VERSION 5.7 ;
  NOWIREEXTENSIONATPIN ON ;
  DIVIDERCHAR "/" ;
  BUSBITCHARS "[]" ;
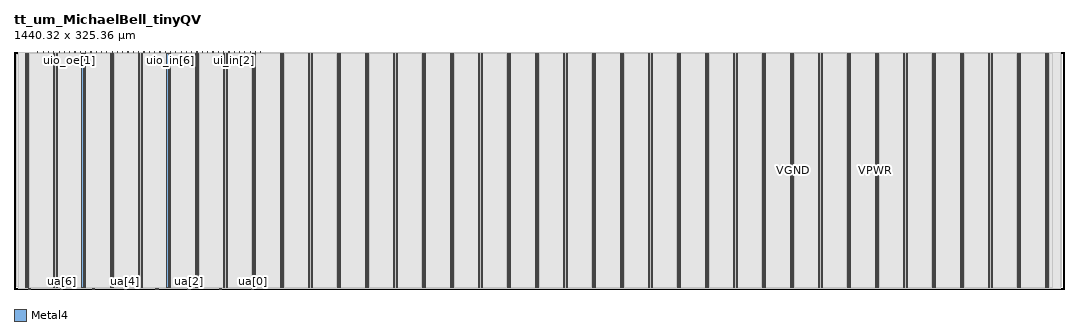
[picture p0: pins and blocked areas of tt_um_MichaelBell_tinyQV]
MACRO tt_um_MichaelBell_tinyQV
  CLASS BLOCK ;
  FOREIGN tt_um_MichaelBell_tinyQV ;
  ORIGIN 0.000 0.000 ;
  SIZE 1440.320 BY 325.360 ;
  PIN VGND
    DIRECTION INOUT ;
    USE GROUND ;
    PORT
      LAYER Metal4 ;
        RECT 18.820 2.000 20.420 323.360 ;
    END
    PORT
      LAYER Metal4 ;
        RECT 57.690 2.000 59.290 323.360 ;
    END
    PORT
      LAYER Metal4 ;
        RECT 96.560 2.000 98.160 323.360 ;
    END
    PORT
      LAYER Metal4 ;
        RECT 135.430 2.000 137.030 323.360 ;
    END
    PORT
      LAYER Metal4 ;
        RECT 174.300 2.000 175.900 323.360 ;
    END
    PORT
      LAYER Metal4 ;
        RECT 213.170 2.000 214.770 323.360 ;
    END
    PORT
      LAYER Metal4 ;
        RECT 252.040 2.000 253.640 323.360 ;
    END
    PORT
      LAYER Metal4 ;
        RECT 290.910 2.000 292.510 323.360 ;
    END
    PORT
      LAYER Metal4 ;
        RECT 329.780 2.000 331.380 323.360 ;
    END
    PORT
      LAYER Metal4 ;
        RECT 368.650 2.000 370.250 323.360 ;
    END
    PORT
      LAYER Metal4 ;
        RECT 407.520 2.000 409.120 323.360 ;
    END
    PORT
      LAYER Metal4 ;
        RECT 446.390 2.000 447.990 323.360 ;
    END
    PORT
      LAYER Metal4 ;
        RECT 485.260 2.000 486.860 323.360 ;
    END
    PORT
      LAYER Metal4 ;
        RECT 524.130 2.000 525.730 323.360 ;
    END
    PORT
      LAYER Metal4 ;
        RECT 563.000 2.000 564.600 323.360 ;
    END
    PORT
      LAYER Metal4 ;
        RECT 601.870 2.000 603.470 323.360 ;
    END
    PORT
      LAYER Metal4 ;
        RECT 640.740 2.000 642.340 323.360 ;
    END
    PORT
      LAYER Metal4 ;
        RECT 679.610 2.000 681.210 323.360 ;
    END
    PORT
      LAYER Metal4 ;
        RECT 718.480 2.000 720.080 323.360 ;
    END
    PORT
      LAYER Metal4 ;
        RECT 757.350 2.000 758.950 323.360 ;
    END
    PORT
      LAYER Metal4 ;
        RECT 796.220 2.000 797.820 323.360 ;
    END
    PORT
      LAYER Metal4 ;
        RECT 835.090 2.000 836.690 323.360 ;
    END
    PORT
      LAYER Metal4 ;
        RECT 873.960 2.000 875.560 323.360 ;
    END
    PORT
      LAYER Metal4 ;
        RECT 912.830 2.000 914.430 323.360 ;
    END
    PORT
      LAYER Metal4 ;
        RECT 951.700 2.000 953.300 323.360 ;
    END
    PORT
      LAYER Metal4 ;
        RECT 990.570 2.000 992.170 323.360 ;
    END
    PORT
      LAYER Metal4 ;
        RECT 1029.440 2.000 1031.040 323.360 ;
    END
    PORT
      LAYER Metal4 ;
        RECT 1068.310 2.000 1069.910 323.360 ;
    END
    PORT
      LAYER Metal4 ;
        RECT 1107.180 2.000 1108.780 323.360 ;
    END
    PORT
      LAYER Metal4 ;
        RECT 1146.050 2.000 1147.650 323.360 ;
    END
    PORT
      LAYER Metal4 ;
        RECT 1184.920 2.000 1186.520 323.360 ;
    END
    PORT
      LAYER Metal4 ;
        RECT 1223.790 2.000 1225.390 323.360 ;
    END
    PORT
      LAYER Metal4 ;
        RECT 1262.660 2.000 1264.260 323.360 ;
    END
    PORT
      LAYER Metal4 ;
        RECT 1301.530 2.000 1303.130 323.360 ;
    END
    PORT
      LAYER Metal4 ;
        RECT 1340.400 2.000 1342.000 323.360 ;
    END
    PORT
      LAYER Metal4 ;
        RECT 1379.270 2.000 1380.870 323.360 ;
    END
    PORT
      LAYER Metal4 ;
        RECT 1418.140 2.000 1419.740 323.360 ;
    END
  END VGND
  PIN VPWR
    DIRECTION INOUT ;
    USE POWER ;
    PORT
      LAYER Metal4 ;
        RECT 15.520 2.000 17.120 323.360 ;
    END
    PORT
      LAYER Metal4 ;
        RECT 54.390 2.000 55.990 323.360 ;
    END
    PORT
      LAYER Metal4 ;
        RECT 93.260 2.000 94.860 323.360 ;
    END
    PORT
      LAYER Metal4 ;
        RECT 132.130 2.000 133.730 323.360 ;
    END
    PORT
      LAYER Metal4 ;
        RECT 171.000 2.000 172.600 323.360 ;
    END
    PORT
      LAYER Metal4 ;
        RECT 209.870 2.000 211.470 323.360 ;
    END
    PORT
      LAYER Metal4 ;
        RECT 248.740 2.000 250.340 323.360 ;
    END
    PORT
      LAYER Metal4 ;
        RECT 287.610 2.000 289.210 323.360 ;
    END
    PORT
      LAYER Metal4 ;
        RECT 326.480 2.000 328.080 323.360 ;
    END
    PORT
      LAYER Metal4 ;
        RECT 365.350 2.000 366.950 323.360 ;
    END
    PORT
      LAYER Metal4 ;
        RECT 404.220 2.000 405.820 323.360 ;
    END
    PORT
      LAYER Metal4 ;
        RECT 443.090 2.000 444.690 323.360 ;
    END
    PORT
      LAYER Metal4 ;
        RECT 481.960 2.000 483.560 323.360 ;
    END
    PORT
      LAYER Metal4 ;
        RECT 520.830 2.000 522.430 323.360 ;
    END
    PORT
      LAYER Metal4 ;
        RECT 559.700 2.000 561.300 323.360 ;
    END
    PORT
      LAYER Metal4 ;
        RECT 598.570 2.000 600.170 323.360 ;
    END
    PORT
      LAYER Metal4 ;
        RECT 637.440 2.000 639.040 323.360 ;
    END
    PORT
      LAYER Metal4 ;
        RECT 676.310 2.000 677.910 323.360 ;
    END
    PORT
      LAYER Metal4 ;
        RECT 715.180 2.000 716.780 323.360 ;
    END
    PORT
      LAYER Metal4 ;
        RECT 754.050 2.000 755.650 323.360 ;
    END
    PORT
      LAYER Metal4 ;
        RECT 792.920 2.000 794.520 323.360 ;
    END
    PORT
      LAYER Metal4 ;
        RECT 831.790 2.000 833.390 323.360 ;
    END
    PORT
      LAYER Metal4 ;
        RECT 870.660 2.000 872.260 323.360 ;
    END
    PORT
      LAYER Metal4 ;
        RECT 909.530 2.000 911.130 323.360 ;
    END
    PORT
      LAYER Metal4 ;
        RECT 948.400 2.000 950.000 323.360 ;
    END
    PORT
      LAYER Metal4 ;
        RECT 987.270 2.000 988.870 323.360 ;
    END
    PORT
      LAYER Metal4 ;
        RECT 1026.140 2.000 1027.740 323.360 ;
    END
    PORT
      LAYER Metal4 ;
        RECT 1065.010 2.000 1066.610 323.360 ;
    END
    PORT
      LAYER Metal4 ;
        RECT 1103.880 2.000 1105.480 323.360 ;
    END
    PORT
      LAYER Metal4 ;
        RECT 1142.750 2.000 1144.350 323.360 ;
    END
    PORT
      LAYER Metal4 ;
        RECT 1181.620 2.000 1183.220 323.360 ;
    END
    PORT
      LAYER Metal4 ;
        RECT 1220.490 2.000 1222.090 323.360 ;
    END
    PORT
      LAYER Metal4 ;
        RECT 1259.360 2.000 1260.960 323.360 ;
    END
    PORT
      LAYER Metal4 ;
        RECT 1298.230 2.000 1299.830 323.360 ;
    END
    PORT
      LAYER Metal4 ;
        RECT 1337.100 2.000 1338.700 323.360 ;
    END
    PORT
      LAYER Metal4 ;
        RECT 1375.970 2.000 1377.570 323.360 ;
    END
    PORT
      LAYER Metal4 ;
        RECT 1414.840 2.000 1416.440 323.360 ;
    END
  END VPWR
  PIN clk
    DIRECTION INPUT ;
    USE SIGNAL ;
    ANTENNAGATEAREA 4.738000 ;
    PORT
      LAYER Metal4 ;
        RECT 331.090 324.360 331.390 325.360 ;
    END
  END clk
  PIN ena
    DIRECTION INPUT ;
    USE SIGNAL ;
    PORT
      LAYER Metal4 ;
        RECT 338.370 324.360 338.670 325.360 ;
    END
  END ena
  PIN rst_n
    DIRECTION INPUT ;
    USE SIGNAL ;
    ANTENNAGATEAREA 1.102000 ;
    PORT
      LAYER Metal4 ;
        RECT 323.810 324.360 324.110 325.360 ;
    END
  END rst_n
  PIN ua[0]
    DIRECTION INOUT ;
    USE SIGNAL ;
    PORT
      LAYER Metal4 ;
        RECT 325.820 0.000 328.820 1.000 ;
    END
  END ua[0]
  PIN ua[1]
    DIRECTION INOUT ;
    USE SIGNAL ;
    PORT
      LAYER Metal4 ;
        RECT 282.140 0.000 285.140 1.000 ;
    END
  END ua[1]
  PIN ua[2]
    DIRECTION INOUT ;
    USE SIGNAL ;
    PORT
      LAYER Metal4 ;
        RECT 238.460 0.000 241.460 1.000 ;
    END
  END ua[2]
  PIN ua[3]
    DIRECTION INOUT ;
    USE SIGNAL ;
    PORT
      LAYER Metal4 ;
        RECT 194.780 0.000 197.780 1.000 ;
    END
  END ua[3]
  PIN ua[4]
    DIRECTION INOUT ;
    USE SIGNAL ;
    PORT
      LAYER Metal4 ;
        RECT 151.100 0.000 154.100 1.000 ;
    END
  END ua[4]
  PIN ua[5]
    DIRECTION INOUT ;
    USE SIGNAL ;
    PORT
      LAYER Metal4 ;
        RECT 107.420 0.000 110.420 1.000 ;
    END
  END ua[5]
  PIN ua[6]
    DIRECTION INOUT ;
    USE SIGNAL ;
    PORT
      LAYER Metal4 ;
        RECT 63.740 0.000 66.740 1.000 ;
    END
  END ua[6]
  PIN ua[7]
    DIRECTION INOUT ;
    USE SIGNAL ;
    PORT
      LAYER Metal4 ;
        RECT 20.060 0.000 23.060 1.000 ;
    END
  END ua[7]
  PIN ui_in[0]
    DIRECTION INPUT ;
    USE SIGNAL ;
    ANTENNAGATEAREA 0.498500 ;
    PORT
      LAYER Metal4 ;
        RECT 316.530 324.360 316.830 325.360 ;
    END
  END ui_in[0]
  PIN ui_in[1]
    DIRECTION INPUT ;
    USE SIGNAL ;
    ANTENNAGATEAREA 0.498500 ;
    PORT
      LAYER Metal4 ;
        RECT 309.250 324.360 309.550 325.360 ;
    END
  END ui_in[1]
  PIN ui_in[2]
    DIRECTION INPUT ;
    USE SIGNAL ;
    ANTENNAGATEAREA 0.498500 ;
    PORT
      LAYER Metal4 ;
        RECT 301.970 324.360 302.270 325.360 ;
    END
  END ui_in[2]
  PIN ui_in[3]
    DIRECTION INPUT ;
    USE SIGNAL ;
    ANTENNAGATEAREA 1.102000 ;
    PORT
      LAYER Metal4 ;
        RECT 294.690 324.360 294.990 325.360 ;
    END
  END ui_in[3]
  PIN ui_in[4]
    DIRECTION INPUT ;
    USE SIGNAL ;
    ANTENNAGATEAREA 1.102000 ;
    PORT
      LAYER Metal4 ;
        RECT 287.410 324.360 287.710 325.360 ;
    END
  END ui_in[4]
  PIN ui_in[5]
    DIRECTION INPUT ;
    USE SIGNAL ;
    ANTENNAGATEAREA 1.102000 ;
    PORT
      LAYER Metal4 ;
        RECT 280.130 324.360 280.430 325.360 ;
    END
  END ui_in[5]
  PIN ui_in[6]
    DIRECTION INPUT ;
    USE SIGNAL ;
    ANTENNAGATEAREA 0.498500 ;
    PORT
      LAYER Metal4 ;
        RECT 272.850 324.360 273.150 325.360 ;
    END
  END ui_in[6]
  PIN ui_in[7]
    DIRECTION INPUT ;
    USE SIGNAL ;
    ANTENNAGATEAREA 0.498500 ;
    PORT
      LAYER Metal4 ;
        RECT 265.570 324.360 265.870 325.360 ;
    END
  END ui_in[7]
  PIN uio_in[0]
    DIRECTION INPUT ;
    USE SIGNAL ;
    PORT
      LAYER Metal4 ;
        RECT 258.290 324.360 258.590 325.360 ;
    END
  END uio_in[0]
  PIN uio_in[1]
    DIRECTION INPUT ;
    USE SIGNAL ;
    ANTENNAGATEAREA 0.498500 ;
    PORT
      LAYER Metal4 ;
        RECT 251.010 324.360 251.310 325.360 ;
    END
  END uio_in[1]
  PIN uio_in[2]
    DIRECTION INPUT ;
    USE SIGNAL ;
    ANTENNAGATEAREA 0.498500 ;
    PORT
      LAYER Metal4 ;
        RECT 243.730 324.360 244.030 325.360 ;
    END
  END uio_in[2]
  PIN uio_in[3]
    DIRECTION INPUT ;
    USE SIGNAL ;
    PORT
      LAYER Metal4 ;
        RECT 236.450 324.360 236.750 325.360 ;
    END
  END uio_in[3]
  PIN uio_in[4]
    DIRECTION INPUT ;
    USE SIGNAL ;
    ANTENNAGATEAREA 0.498500 ;
    PORT
      LAYER Metal4 ;
        RECT 229.170 324.360 229.470 325.360 ;
    END
  END uio_in[4]
  PIN uio_in[5]
    DIRECTION INPUT ;
    USE SIGNAL ;
    ANTENNAGATEAREA 0.498500 ;
    PORT
      LAYER Metal4 ;
        RECT 221.890 324.360 222.190 325.360 ;
    END
  END uio_in[5]
  PIN uio_in[6]
    DIRECTION INPUT ;
    USE SIGNAL ;
    PORT
      LAYER Metal4 ;
        RECT 214.610 324.360 214.910 325.360 ;
    END
  END uio_in[6]
  PIN uio_in[7]
    DIRECTION INPUT ;
    USE SIGNAL ;
    PORT
      LAYER Metal4 ;
        RECT 207.330 324.360 207.630 325.360 ;
    END
  END uio_in[7]
  PIN uio_oe[0]
    DIRECTION OUTPUT ;
    USE SIGNAL ;
    ANTENNADIFFAREA 1.182800 ;
    PORT
      LAYER Metal4 ;
        RECT 83.570 324.360 83.870 325.360 ;
    END
  END uio_oe[0]
  PIN uio_oe[1]
    DIRECTION OUTPUT ;
    USE SIGNAL ;
    ANTENNADIFFAREA 3.879200 ;
    PORT
      LAYER Metal4 ;
        RECT 76.290 324.360 76.590 325.360 ;
    END
  END uio_oe[1]
  PIN uio_oe[2]
    DIRECTION OUTPUT ;
    USE SIGNAL ;
    ANTENNAGATEAREA 0.741000 ;
    ANTENNADIFFAREA 2.080400 ;
    PORT
      LAYER Metal4 ;
        RECT 69.010 324.360 69.310 325.360 ;
    END
  END uio_oe[2]
  PIN uio_oe[3]
    DIRECTION OUTPUT ;
    USE SIGNAL ;
    ANTENNADIFFAREA 1.182800 ;
    PORT
      LAYER Metal4 ;
        RECT 61.730 324.360 62.030 325.360 ;
    END
  END uio_oe[3]
  PIN uio_oe[4]
    DIRECTION OUTPUT ;
    USE SIGNAL ;
    ANTENNADIFFAREA 1.182800 ;
    PORT
      LAYER Metal4 ;
        RECT 54.450 324.360 54.750 325.360 ;
    END
  END uio_oe[4]
  PIN uio_oe[5]
    DIRECTION OUTPUT ;
    USE SIGNAL ;
    ANTENNADIFFAREA 1.182800 ;
    PORT
      LAYER Metal4 ;
        RECT 47.170 324.360 47.470 325.360 ;
    END
  END uio_oe[5]
  PIN uio_oe[6]
    DIRECTION OUTPUT ;
    USE SIGNAL ;
    ANTENNADIFFAREA 1.182800 ;
    PORT
      LAYER Metal4 ;
        RECT 39.890 324.360 40.190 325.360 ;
    END
  END uio_oe[6]
  PIN uio_oe[7]
    DIRECTION OUTPUT ;
    USE SIGNAL ;
    ANTENNADIFFAREA 1.182800 ;
    PORT
      LAYER Metal4 ;
        RECT 32.610 324.360 32.910 325.360 ;
    END
  END uio_oe[7]
  PIN uio_out[0]
    DIRECTION OUTPUT ;
    USE SIGNAL ;
    ANTENNADIFFAREA 1.182800 ;
    PORT
      LAYER Metal4 ;
        RECT 141.810 324.360 142.110 325.360 ;
    END
  END uio_out[0]
  PIN uio_out[1]
    DIRECTION OUTPUT ;
    USE SIGNAL ;
    ANTENNADIFFAREA 1.366000 ;
    PORT
      LAYER Metal4 ;
        RECT 134.530 324.360 134.830 325.360 ;
    END
  END uio_out[1]
  PIN uio_out[2]
    DIRECTION OUTPUT ;
    USE SIGNAL ;
    ANTENNADIFFAREA 1.366000 ;
    PORT
      LAYER Metal4 ;
        RECT 127.250 324.360 127.550 325.360 ;
    END
  END uio_out[2]
  PIN uio_out[3]
    DIRECTION OUTPUT ;
    USE SIGNAL ;
    ANTENNADIFFAREA 1.182800 ;
    PORT
      LAYER Metal4 ;
        RECT 119.970 324.360 120.270 325.360 ;
    END
  END uio_out[3]
  PIN uio_out[4]
    DIRECTION OUTPUT ;
    USE SIGNAL ;
    ANTENNADIFFAREA 2.932000 ;
    PORT
      LAYER Metal4 ;
        RECT 112.690 324.360 112.990 325.360 ;
    END
  END uio_out[4]
  PIN uio_out[5]
    DIRECTION OUTPUT ;
    USE SIGNAL ;
    ANTENNADIFFAREA 1.366000 ;
    PORT
      LAYER Metal4 ;
        RECT 105.410 324.360 105.710 325.360 ;
    END
  END uio_out[5]
  PIN uio_out[6]
    DIRECTION OUTPUT ;
    USE SIGNAL ;
    ANTENNADIFFAREA 1.182800 ;
    PORT
      LAYER Metal4 ;
        RECT 98.130 324.360 98.430 325.360 ;
    END
  END uio_out[6]
  PIN uio_out[7]
    DIRECTION OUTPUT ;
    USE SIGNAL ;
    ANTENNADIFFAREA 4.389000 ;
    PORT
      LAYER Metal4 ;
        RECT 90.850 324.360 91.150 325.360 ;
    END
  END uio_out[7]
  PIN uo_out[0]
    DIRECTION OUTPUT ;
    USE SIGNAL ;
    ANTENNADIFFAREA 4.369000 ;
    PORT
      LAYER Metal4 ;
        RECT 200.050 324.360 200.350 325.360 ;
    END
  END uo_out[0]
  PIN uo_out[1]
    DIRECTION OUTPUT ;
    USE SIGNAL ;
    ANTENNADIFFAREA 4.369000 ;
    PORT
      LAYER Metal4 ;
        RECT 192.770 324.360 193.070 325.360 ;
    END
  END uo_out[1]
  PIN uo_out[2]
    DIRECTION OUTPUT ;
    USE SIGNAL ;
    ANTENNADIFFAREA 1.121800 ;
    PORT
      LAYER Metal4 ;
        RECT 185.490 324.360 185.790 325.360 ;
    END
  END uo_out[2]
  PIN uo_out[3]
    DIRECTION OUTPUT ;
    USE SIGNAL ;
    ANTENNADIFFAREA 1.121800 ;
    PORT
      LAYER Metal4 ;
        RECT 178.210 324.360 178.510 325.360 ;
    END
  END uo_out[3]
  PIN uo_out[4]
    DIRECTION OUTPUT ;
    USE SIGNAL ;
    ANTENNADIFFAREA 1.121800 ;
    PORT
      LAYER Metal4 ;
        RECT 170.930 324.360 171.230 325.360 ;
    END
  END uo_out[4]
  PIN uo_out[5]
    DIRECTION OUTPUT ;
    USE SIGNAL ;
    ANTENNADIFFAREA 1.121800 ;
    PORT
      LAYER Metal4 ;
        RECT 163.650 324.360 163.950 325.360 ;
    END
  END uo_out[5]
  PIN uo_out[6]
    DIRECTION OUTPUT ;
    USE SIGNAL ;
    ANTENNADIFFAREA 1.366000 ;
    PORT
      LAYER Metal4 ;
        RECT 156.370 324.360 156.670 325.360 ;
    END
  END uo_out[6]
  PIN uo_out[7]
    DIRECTION OUTPUT ;
    USE SIGNAL ;
    ANTENNADIFFAREA 1.121800 ;
    PORT
      LAYER Metal4 ;
        RECT 149.090 324.360 149.390 325.360 ;
    END
  END uo_out[7]
  OBS
      LAYER Nwell ;
        RECT 2.930 319.280 1437.390 321.870 ;
      LAYER Pwell ;
        RECT 2.930 315.760 1437.390 319.280 ;
      LAYER Nwell ;
        RECT 2.930 311.440 1437.390 315.760 ;
      LAYER Pwell ;
        RECT 2.930 307.920 1437.390 311.440 ;
      LAYER Nwell ;
        RECT 2.930 303.600 1437.390 307.920 ;
      LAYER Pwell ;
        RECT 2.930 300.080 1437.390 303.600 ;
      LAYER Nwell ;
        RECT 2.930 295.760 1437.390 300.080 ;
      LAYER Pwell ;
        RECT 2.930 292.240 1437.390 295.760 ;
      LAYER Nwell ;
        RECT 2.930 287.920 1437.390 292.240 ;
      LAYER Pwell ;
        RECT 2.930 284.400 1437.390 287.920 ;
      LAYER Nwell ;
        RECT 2.930 280.080 1437.390 284.400 ;
      LAYER Pwell ;
        RECT 2.930 276.560 1437.390 280.080 ;
      LAYER Nwell ;
        RECT 2.930 272.240 1437.390 276.560 ;
      LAYER Pwell ;
        RECT 2.930 268.720 1437.390 272.240 ;
      LAYER Nwell ;
        RECT 2.930 264.400 1437.390 268.720 ;
      LAYER Pwell ;
        RECT 2.930 260.880 1437.390 264.400 ;
      LAYER Nwell ;
        RECT 2.930 256.560 1437.390 260.880 ;
      LAYER Pwell ;
        RECT 2.930 253.040 1437.390 256.560 ;
      LAYER Nwell ;
        RECT 2.930 248.720 1437.390 253.040 ;
      LAYER Pwell ;
        RECT 2.930 245.200 1437.390 248.720 ;
      LAYER Nwell ;
        RECT 2.930 240.880 1437.390 245.200 ;
      LAYER Pwell ;
        RECT 2.930 237.360 1437.390 240.880 ;
      LAYER Nwell ;
        RECT 2.930 233.040 1437.390 237.360 ;
      LAYER Pwell ;
        RECT 2.930 229.520 1437.390 233.040 ;
      LAYER Nwell ;
        RECT 2.930 225.200 1437.390 229.520 ;
      LAYER Pwell ;
        RECT 2.930 221.680 1437.390 225.200 ;
      LAYER Nwell ;
        RECT 2.930 217.360 1437.390 221.680 ;
      LAYER Pwell ;
        RECT 2.930 213.840 1437.390 217.360 ;
      LAYER Nwell ;
        RECT 2.930 209.520 1437.390 213.840 ;
      LAYER Pwell ;
        RECT 2.930 206.000 1437.390 209.520 ;
      LAYER Nwell ;
        RECT 2.930 201.680 1437.390 206.000 ;
      LAYER Pwell ;
        RECT 2.930 198.160 1437.390 201.680 ;
      LAYER Nwell ;
        RECT 2.930 193.840 1437.390 198.160 ;
      LAYER Pwell ;
        RECT 2.930 190.320 1437.390 193.840 ;
      LAYER Nwell ;
        RECT 2.930 186.000 1437.390 190.320 ;
      LAYER Pwell ;
        RECT 2.930 182.480 1437.390 186.000 ;
      LAYER Nwell ;
        RECT 2.930 178.160 1437.390 182.480 ;
      LAYER Pwell ;
        RECT 2.930 174.640 1437.390 178.160 ;
      LAYER Nwell ;
        RECT 2.930 170.320 1437.390 174.640 ;
      LAYER Pwell ;
        RECT 2.930 166.800 1437.390 170.320 ;
      LAYER Nwell ;
        RECT 2.930 162.480 1437.390 166.800 ;
      LAYER Pwell ;
        RECT 2.930 158.960 1437.390 162.480 ;
      LAYER Nwell ;
        RECT 2.930 154.640 1437.390 158.960 ;
      LAYER Pwell ;
        RECT 2.930 151.120 1437.390 154.640 ;
      LAYER Nwell ;
        RECT 2.930 146.800 1437.390 151.120 ;
      LAYER Pwell ;
        RECT 2.930 143.280 1437.390 146.800 ;
      LAYER Nwell ;
        RECT 2.930 138.960 1437.390 143.280 ;
      LAYER Pwell ;
        RECT 2.930 135.440 1437.390 138.960 ;
      LAYER Nwell ;
        RECT 2.930 131.120 1437.390 135.440 ;
      LAYER Pwell ;
        RECT 2.930 127.600 1437.390 131.120 ;
      LAYER Nwell ;
        RECT 2.930 123.280 1437.390 127.600 ;
      LAYER Pwell ;
        RECT 2.930 119.760 1437.390 123.280 ;
      LAYER Nwell ;
        RECT 2.930 115.440 1437.390 119.760 ;
      LAYER Pwell ;
        RECT 2.930 111.920 1437.390 115.440 ;
      LAYER Nwell ;
        RECT 2.930 107.600 1437.390 111.920 ;
      LAYER Pwell ;
        RECT 2.930 104.080 1437.390 107.600 ;
      LAYER Nwell ;
        RECT 2.930 99.760 1437.390 104.080 ;
      LAYER Pwell ;
        RECT 2.930 96.240 1437.390 99.760 ;
      LAYER Nwell ;
        RECT 2.930 91.920 1437.390 96.240 ;
      LAYER Pwell ;
        RECT 2.930 88.400 1437.390 91.920 ;
      LAYER Nwell ;
        RECT 2.930 84.080 1437.390 88.400 ;
      LAYER Pwell ;
        RECT 2.930 80.560 1437.390 84.080 ;
      LAYER Nwell ;
        RECT 2.930 76.240 1437.390 80.560 ;
      LAYER Pwell ;
        RECT 2.930 72.720 1437.390 76.240 ;
      LAYER Nwell ;
        RECT 2.930 68.400 1437.390 72.720 ;
      LAYER Pwell ;
        RECT 2.930 66.210 1437.390 68.400 ;
        RECT 2.930 64.880 266.430 66.210 ;
      LAYER Nwell ;
        RECT 266.430 64.880 1437.390 66.210 ;
        RECT 2.930 60.560 1437.390 64.880 ;
      LAYER Pwell ;
        RECT 2.930 57.040 266.430 60.560 ;
      LAYER Nwell ;
        RECT 266.430 57.040 1437.390 60.560 ;
        RECT 2.930 52.720 1437.390 57.040 ;
      LAYER Pwell ;
        RECT 2.930 49.200 266.430 52.720 ;
      LAYER Nwell ;
        RECT 266.430 49.200 1437.390 52.720 ;
        RECT 2.930 44.880 1437.390 49.200 ;
      LAYER Pwell ;
        RECT 2.930 41.360 266.430 44.880 ;
      LAYER Nwell ;
        RECT 266.430 41.360 1437.390 44.880 ;
        RECT 2.930 37.040 1437.390 41.360 ;
      LAYER Pwell ;
        RECT 2.930 33.520 266.430 37.040 ;
      LAYER Nwell ;
        RECT 266.430 33.520 1437.390 37.040 ;
        RECT 2.930 29.200 1437.390 33.520 ;
      LAYER Pwell ;
        RECT 2.930 25.680 266.430 29.200 ;
      LAYER Nwell ;
        RECT 266.430 25.680 1437.390 29.200 ;
        RECT 2.930 21.360 1437.390 25.680 ;
      LAYER Pwell ;
        RECT 2.930 17.840 266.430 21.360 ;
      LAYER Nwell ;
        RECT 266.430 17.840 1437.390 21.360 ;
        RECT 2.930 13.520 1437.390 17.840 ;
      LAYER Pwell ;
        RECT 2.930 10.000 266.430 13.520 ;
      LAYER Nwell ;
        RECT 266.430 10.000 1437.390 13.520 ;
        RECT 2.930 5.680 1437.390 10.000 ;
      LAYER Pwell ;
        RECT 2.930 3.490 266.430 5.680 ;
      LAYER Nwell ;
        RECT 266.430 3.490 1437.390 5.680 ;
      LAYER Metal1 ;
        RECT 3.360 3.620 1436.960 321.740 ;
      LAYER Metal2 ;
        RECT 5.740 1.210 1435.140 324.710 ;
      LAYER Metal3 ;
        RECT 5.690 1.260 1435.190 324.660 ;
      LAYER Metal4 ;
        RECT 17.500 324.060 32.310 324.360 ;
        RECT 33.210 324.060 39.590 324.360 ;
        RECT 40.490 324.060 46.870 324.360 ;
        RECT 47.770 324.060 54.150 324.360 ;
        RECT 55.050 324.060 61.430 324.360 ;
        RECT 62.330 324.060 68.710 324.360 ;
        RECT 69.610 324.060 75.990 324.360 ;
        RECT 76.890 324.060 83.270 324.360 ;
        RECT 84.170 324.060 90.550 324.360 ;
        RECT 91.450 324.060 97.830 324.360 ;
        RECT 98.730 324.060 105.110 324.360 ;
        RECT 106.010 324.060 112.390 324.360 ;
        RECT 113.290 324.060 119.670 324.360 ;
        RECT 120.570 324.060 126.950 324.360 ;
        RECT 127.850 324.060 134.230 324.360 ;
        RECT 135.130 324.060 141.510 324.360 ;
        RECT 142.410 324.060 148.790 324.360 ;
        RECT 149.690 324.060 156.070 324.360 ;
        RECT 156.970 324.060 163.350 324.360 ;
        RECT 164.250 324.060 170.630 324.360 ;
        RECT 171.530 324.060 177.910 324.360 ;
        RECT 178.810 324.060 185.190 324.360 ;
        RECT 186.090 324.060 192.470 324.360 ;
        RECT 193.370 324.060 199.750 324.360 ;
        RECT 200.650 324.060 207.030 324.360 ;
        RECT 207.930 324.060 214.310 324.360 ;
        RECT 215.210 324.060 221.590 324.360 ;
        RECT 222.490 324.060 228.870 324.360 ;
        RECT 229.770 324.060 236.150 324.360 ;
        RECT 237.050 324.060 243.430 324.360 ;
        RECT 244.330 324.060 250.710 324.360 ;
        RECT 251.610 324.060 257.990 324.360 ;
        RECT 258.890 324.060 265.270 324.360 ;
        RECT 266.170 324.060 272.550 324.360 ;
        RECT 273.450 324.060 279.830 324.360 ;
        RECT 280.730 324.060 287.110 324.360 ;
        RECT 288.010 324.060 294.390 324.360 ;
        RECT 295.290 324.060 301.670 324.360 ;
        RECT 302.570 324.060 308.950 324.360 ;
        RECT 309.850 324.060 316.230 324.360 ;
        RECT 317.130 324.060 323.510 324.360 ;
        RECT 324.410 324.060 330.790 324.360 ;
        RECT 331.690 324.060 338.070 324.360 ;
        RECT 338.970 324.060 1425.060 324.360 ;
        RECT 17.500 323.660 1425.060 324.060 ;
        RECT 17.500 1.700 18.520 323.660 ;
        RECT 20.720 1.700 54.090 323.660 ;
        RECT 56.290 1.700 57.390 323.660 ;
        RECT 59.590 1.700 92.960 323.660 ;
        RECT 95.160 1.700 96.260 323.660 ;
        RECT 98.460 1.700 131.830 323.660 ;
        RECT 134.030 1.700 135.130 323.660 ;
        RECT 137.330 1.700 170.700 323.660 ;
        RECT 172.900 1.700 174.000 323.660 ;
        RECT 176.200 1.700 209.570 323.660 ;
        RECT 211.770 1.700 212.870 323.660 ;
        RECT 215.070 1.700 248.440 323.660 ;
        RECT 250.640 1.700 251.740 323.660 ;
        RECT 253.940 1.700 287.310 323.660 ;
        RECT 289.510 1.700 290.610 323.660 ;
        RECT 292.810 1.700 326.180 323.660 ;
        RECT 328.380 1.700 329.480 323.660 ;
        RECT 331.680 1.700 365.050 323.660 ;
        RECT 367.250 1.700 368.350 323.660 ;
        RECT 370.550 1.700 403.920 323.660 ;
        RECT 406.120 1.700 407.220 323.660 ;
        RECT 409.420 1.700 442.790 323.660 ;
        RECT 444.990 1.700 446.090 323.660 ;
        RECT 448.290 1.700 481.660 323.660 ;
        RECT 483.860 1.700 484.960 323.660 ;
        RECT 487.160 1.700 520.530 323.660 ;
        RECT 522.730 1.700 523.830 323.660 ;
        RECT 526.030 1.700 559.400 323.660 ;
        RECT 561.600 1.700 562.700 323.660 ;
        RECT 564.900 1.700 598.270 323.660 ;
        RECT 600.470 1.700 601.570 323.660 ;
        RECT 603.770 1.700 637.140 323.660 ;
        RECT 639.340 1.700 640.440 323.660 ;
        RECT 642.640 1.700 676.010 323.660 ;
        RECT 678.210 1.700 679.310 323.660 ;
        RECT 681.510 1.700 714.880 323.660 ;
        RECT 717.080 1.700 718.180 323.660 ;
        RECT 720.380 1.700 753.750 323.660 ;
        RECT 755.950 1.700 757.050 323.660 ;
        RECT 759.250 1.700 792.620 323.660 ;
        RECT 794.820 1.700 795.920 323.660 ;
        RECT 798.120 1.700 831.490 323.660 ;
        RECT 833.690 1.700 834.790 323.660 ;
        RECT 836.990 1.700 870.360 323.660 ;
        RECT 872.560 1.700 873.660 323.660 ;
        RECT 875.860 1.700 909.230 323.660 ;
        RECT 911.430 1.700 912.530 323.660 ;
        RECT 914.730 1.700 948.100 323.660 ;
        RECT 950.300 1.700 951.400 323.660 ;
        RECT 953.600 1.700 986.970 323.660 ;
        RECT 989.170 1.700 990.270 323.660 ;
        RECT 992.470 1.700 1025.840 323.660 ;
        RECT 1028.040 1.700 1029.140 323.660 ;
        RECT 1031.340 1.700 1064.710 323.660 ;
        RECT 1066.910 1.700 1068.010 323.660 ;
        RECT 1070.210 1.700 1103.580 323.660 ;
        RECT 1105.780 1.700 1106.880 323.660 ;
        RECT 1109.080 1.700 1142.450 323.660 ;
        RECT 1144.650 1.700 1145.750 323.660 ;
        RECT 1147.950 1.700 1181.320 323.660 ;
        RECT 1183.520 1.700 1184.620 323.660 ;
        RECT 1186.820 1.700 1220.190 323.660 ;
        RECT 1222.390 1.700 1223.490 323.660 ;
        RECT 1225.690 1.700 1259.060 323.660 ;
        RECT 1261.260 1.700 1262.360 323.660 ;
        RECT 1264.560 1.700 1297.930 323.660 ;
        RECT 1300.130 1.700 1301.230 323.660 ;
        RECT 1303.430 1.700 1336.800 323.660 ;
        RECT 1339.000 1.700 1340.100 323.660 ;
        RECT 1342.300 1.700 1375.670 323.660 ;
        RECT 1377.870 1.700 1378.970 323.660 ;
        RECT 1381.170 1.700 1414.540 323.660 ;
        RECT 1416.740 1.700 1417.840 323.660 ;
        RECT 1420.040 1.700 1425.060 323.660 ;
        RECT 17.500 1.300 1425.060 1.700 ;
        RECT 17.500 1.000 19.760 1.300 ;
        RECT 23.360 1.000 63.440 1.300 ;
        RECT 67.040 1.000 107.120 1.300 ;
        RECT 110.720 1.000 150.800 1.300 ;
        RECT 154.400 1.000 194.480 1.300 ;
        RECT 198.080 1.000 238.160 1.300 ;
        RECT 241.760 1.000 281.840 1.300 ;
        RECT 285.440 1.000 325.520 1.300 ;
        RECT 329.120 1.000 1425.060 1.300 ;
  END
END tt_um_MichaelBell_tinyQV
END LIBRARY

